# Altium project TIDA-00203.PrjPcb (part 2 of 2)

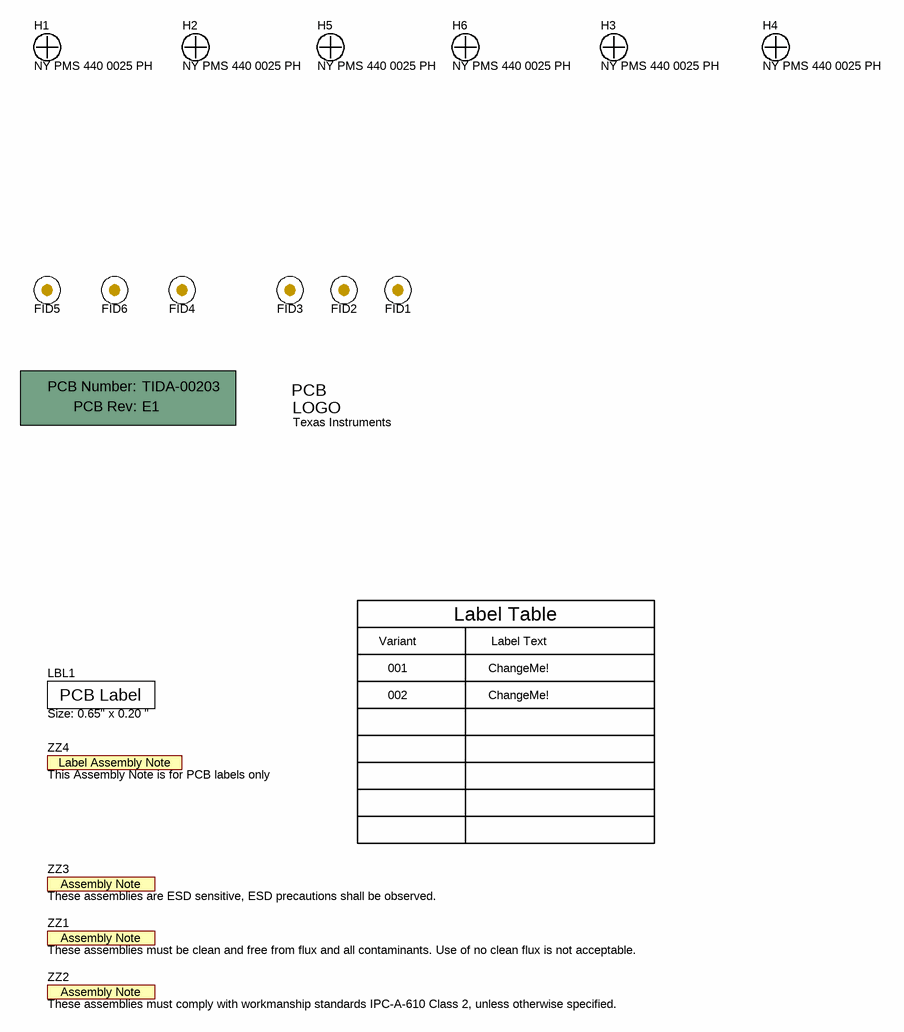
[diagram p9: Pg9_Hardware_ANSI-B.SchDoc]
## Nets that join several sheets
3.3V: Pg3_MICROCONTROLLER (36 pins), Pg4_10_100_ETHERNET_USB (13 pins), Pg5_CAN_RS485 (10 pins), Pg6_MII_RMII_INTERFACE (C44.1 R57.2 U6.3 U6.4), Pg7_POWER_SUPPLY (6 pins), Pg8_SPARE_AND_DEBUG (6 pins)
+5V: Pg4_10_100_ETHERNET_USB (C21.1 U3.5), Pg5_CAN_RS485 (C30.2 U4.3), Pg6_MII_RMII_INTERFACE (D10.1 D11.3 R62.1), Pg7_POWER_SUPPLY (6 pins)
GNDX: Pg3_MICROCONTROLLER (64 pins), Pg4_10_100_ETHERNET_USB (22 pins), Pg5_CAN_RS485 (13 pins), Pg6_MII_RMII_INTERFACE (10 pins), Pg7_POWER_SUPPLY (14 pins), Pg8_SPARE_AND_DEBUG (J7.5 J7.7 J7.9)
EXTDB~{G}: Pg3_MICROCONTROLLER (U2.A4), Pg8_SPARE_AND_DEBUG (J7.3 R18.2)
HI~{B}: Pg3_MICROCONTROLLER (U2.M17), Pg7_POWER_SUPPLY (R49.1)
ADC0: Pg3_MICROCONTROLLER (U2.G2), Pg8_SPARE_AND_DEBUG (J3.10)
ADC1: Pg3_MICROCONTROLLER (U2.G1), Pg8_SPARE_AND_DEBUG (J3.8)
ADC2: Pg3_MICROCONTROLLER (U2.H2), Pg8_SPARE_AND_DEBUG (J3.6)
ADC3: Pg3_MICROCONTROLLER (U2.H3), Pg8_SPARE_AND_DEBUG (J3.4)
CAN0RX: Pg3_MICROCONTROLLER (U2.W10), Pg6_MII_RMII_INTERFACE (J9.18 TP7.1)
CAN0TX: Pg3_MICROCONTROLLER (U2.V10), Pg6_MII_RMII_INTERFACE (J9.20 TP14.1)
CAN1RX: Pg3_MICROCONTROLLER (U2.E18), Pg5_CAN_RS485 (J10.1 U4.4)
CAN1TX: Pg3_MICROCONTROLLER (U2.F17), Pg5_CAN_RS485 (J10.2 U4.1)
COL: Pg3_MICROCONTROLLER (U2.N18), Pg6_MII_RMII_INTERFACE (J9.15)
CRS: Pg3_MICROCONTROLLER (U2.N19), Pg6_MII_RMII_INTERFACE (J9.17)
DEBUG_RX: Pg3_MICROCONTROLLER (U2.V3), Pg8_SPARE_AND_DEBUG (J4.1)
DEBUG_TX: Pg3_MICROCONTROLLER (R3.2 U2.W3), Pg8_SPARE_AND_DEBUG (J4.2)
EN0INTRN: Pg3_MICROCONTROLLER (U2.D6), Pg6_MII_RMII_INTERFACE (J9.41)
EN0TXER: Pg3_MICROCONTROLLER (U2.T12), Pg6_MII_RMII_INTERFACE (J9.42 TP9.1)
I2C6SCL: Pg3_MICROCONTROLLER (R2.2 U2.F2), Pg8_SPARE_AND_DEBUG (J3.9)
I2C6SDA: Pg3_MICROCONTROLLER (R1.2 U2.F1), Pg8_SPARE_AND_DEBUG (J3.2)
I2C8SCL: Pg3_MICROCONTROLLER (R59.2 U2.D2), Pg6_MII_RMII_INTERFACE (J9.6 TP4.1)
I2C8SDA: Pg3_MICROCONTROLLER (R61.2 U2.D1), Pg6_MII_RMII_INTERFACE (J9.8 TP2.1)
MCU_ISENSE: Pg3_MICROCONTROLLER (U2.A7), Pg6_MII_RMII_INTERFACE (U6.1)
MDC: Pg3_MICROCONTROLLER (U2.W6), Pg6_MII_RMII_INTERFACE (J9.21)
MDIO: Pg3_MICROCONTROLLER (U2.T7), Pg6_MII_RMII_INTERFACE (J9.19)
PF1/LED2: Pg3_MICROCONTROLLER (U2.V6), Pg4_10_100_ETHERNET_USB (R48.1)
PG0/PPS: Pg3_MICROCONTROLLER (U2.N15), Pg6_MII_RMII_INTERFACE (J9.43)
RESET_N: Pg3_MICROCONTROLLER (U2.B9), Pg6_MII_RMII_INTERFACE (J9.22 TP6.1)
RX_CLK: Pg3_MICROCONTROLLER (U2.V5), Pg6_MII_RMII_INTERFACE (J9.37)
RX_DV: Pg3_MICROCONTROLLER (U2.U14), Pg6_MII_RMII_INTERFACE (J9.35)
RX_ER: Pg3_MICROCONTROLLER (U2.V12), Pg6_MII_RMII_INTERFACE (J9.39)
RXD0: Pg3_MICROCONTROLLER (U2.W12), Pg6_MII_RMII_INTERFACE (J9.31)
RXD1: Pg3_MICROCONTROLLER (U2.U15), Pg6_MII_RMII_INTERFACE (J9.33)
RXD2: Pg3_MICROCONTROLLER (U2.V17), Pg6_MII_RMII_INTERFACE (J9.29)
RXD3: Pg3_MICROCONTROLLER (U2.U19), Pg4_10_100_ETHERNET_USB (R24.1), Pg6_MII_RMII_INTERFACE (J9.27)
SPARE1: Pg3_MICROCONTROLLER (U2.V7), Pg8_SPARE_AND_DEBUG (J3.1)
SPARE2: Pg3_MICROCONTROLLER (U2.W7), Pg8_SPARE_AND_DEBUG (J3.3)
SPARE3: Pg3_MICROCONTROLLER (U2.R3), Pg8_SPARE_AND_DEBUG (J3.5)
SPARE4: Pg3_MICROCONTROLLER (U2.D7), Pg8_SPARE_AND_DEBUG (J3.7)
SPI0CS: Pg3_MICROCONTROLLER (U2.U5), Pg6_MII_RMII_INTERFACE (J9.26 TP13.1)
SPI0SCK: Pg3_MICROCONTROLLER (U2.T6), Pg6_MII_RMII_INTERFACE (J9.28 TP12.1)
SPI0SDI: Pg3_MICROCONTROLLER (U2.W4), Pg6_MII_RMII_INTERFACE (J9.32 TP18.1)
SPI0SDO: Pg3_MICROCONTROLLER (R60.2 U2.V4), Pg6_MII_RMII_INTERFACE (J9.30 TP17.1)
SPI3CS: Pg3_MICROCONTROLLER (U2.E2), Pg6_MII_RMII_INTERFACE (J9.10 TP1.1)
SPI3SCK: Pg3_MICROCONTROLLER (U2.E3), Pg6_MII_RMII_INTERFACE (J9.12 TP3.1)
SPI3SDI: Pg3_MICROCONTROLLER (U2.U6), Pg6_MII_RMII_INTERFACE (J9.16 TP8.1)
SPI3SDO: Pg3_MICROCONTROLLER (U2.H4), Pg6_MII_RMII_INTERFACE (J9.14 TP5.1)
T_TRST: Pg3_MICROCONTROLLER (R38.2), Pg8_SPARE_AND_DEBUG (J7.10)
TCK: Pg3_MICROCONTROLLER (U2.B15), Pg8_SPARE_AND_DEBUG (J7.4 R20.2)
TDI: Pg3_MICROCONTROLLER (U2.D14), Pg8_SPARE_AND_DEBUG (J7.8 R52.2)
TDO: Pg3_MICROCONTROLLER (U2.C14), Pg8_SPARE_AND_DEBUG (J7.6 R54.2)
TMS: Pg3_MICROCONTROLLER (U2.C15), Pg8_SPARE_AND_DEBUG (J7.2 R17.2)
TX_CLK: Pg3_MICROCONTROLLER (R43.2 U2.V11), Pg6_MII_RMII_INTERFACE (J9.25)
TX_EN: Pg3_MICROCONTROLLER (R46.2), Pg6_MII_RMII_INTERFACE (J9.5)
TXD0: Pg3_MICROCONTROLLER (C45.2 R40.2), Pg6_MII_RMII_INTERFACE (J9.7)
TXD1: Pg3_MICROCONTROLLER (C46.2 R47.2), Pg6_MII_RMII_INTERFACE (J9.9)
TXD2: Pg3_MICROCONTROLLER (C47.2 R6.2), Pg4_10_100_ETHERNET_USB (R23.1), Pg6_MII_RMII_INTERFACE (J9.11)
TXD3: Pg3_MICROCONTROLLER (C48.2 R8.2), Pg6_MII_RMII_INTERFACE (J9.13)
U3RTS: Pg3_MICROCONTROLLER (U2.F18), Pg5_CAN_RS485 (J10.4 U1.2 U1.3)
U3RX: Pg3_MICROCONTROLLER (U2.C8), Pg5_CAN_RS485 (J10.5 U1.1)
U3TX: Pg3_MICROCONTROLLER (U2.E7), Pg5_CAN_RS485 (J10.3 U1.4)
U5RX: Pg3_MICROCONTROLLER (U2.U2), Pg6_MII_RMII_INTERFACE (J9.36 TP16.1)
U5TX: Pg3_MICROCONTROLLER (U2.V2), Pg6_MII_RMII_INTERFACE (J9.34 TP15.1)
U7RX: Pg3_MICROCONTROLLER (U2.M2), Pg6_MII_RMII_INTERFACE (J9.40 TP10.1)
U7TX: Pg3_MICROCONTROLLER (U2.M1), Pg6_MII_RMII_INTERFACE (J9.38 TP11.1)
USB0DM: Pg3_MICROCONTROLLER (U2.B18), Pg4_10_100_ETHERNET_USB (D5.1 J5.2)
USB0DP: Pg3_MICROCONTROLLER (U2.C18), Pg4_10_100_ETHERNET_USB (D4.1 J5.3)
USB0EPEN: Pg3_MICROCONTROLLER (U2.B3), Pg4_10_100_ETHERNET_USB (R14.2 TP19.1)
USB0ID: Pg3_MICROCONTROLLER (U2.A16), Pg4_10_100_ETHERNET_USB (R35.2)
USB0PLFT: Pg3_MICROCONTROLLER (U2.B2), Pg4_10_100_ETHERNET_USB (R15.2 TP20.1)
USB0VBUS: Pg3_MICROCONTROLLER (U2.B16), Pg4_10_100_ETHERNET_USB (R36.2)

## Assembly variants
001: not fitted J10 R5 R43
